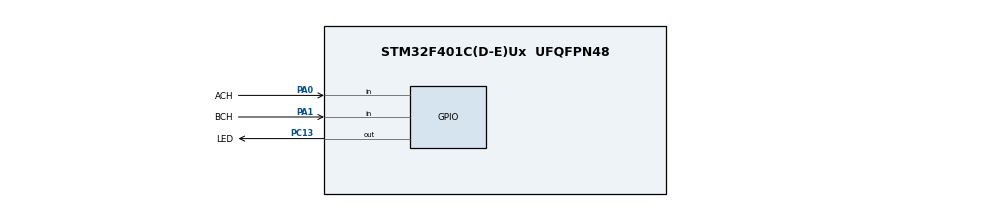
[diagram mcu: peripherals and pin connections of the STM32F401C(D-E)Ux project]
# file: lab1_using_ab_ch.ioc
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Mcu.Family=STM32F4
Mcu.Name=STM32F401C(D-E)Ux
Mcu.Package=UFQFPN48
NVIC.PriorityGroup=NVIC_PRIORITYGROUP_4
PA0-WKUP.GPIO_Label=ACH
PA0-WKUP.Signal=GPIO_Input
PA1.GPIO_Label=BCH
PA1.Signal=GPIO_Input
PA13.Mode=Serial_Wire
PA13.Signal=SYS_JTMS-SWDIO
PA14.Mode=Serial_Wire
PA14.Signal=SYS_JTCK-SWCLK
PC13-ANTI_TAMP.GPIO_Label=LED
PC13-ANTI_TAMP.Signal=GPIO_Output
PH0\ -\ OSC_IN.Mode=HSE-External-Oscillator
PH0\ -\ OSC_IN.Signal=RCC_OSC_IN
PH1\ -\ OSC_OUT.Mode=HSE-External-Oscillator
PH1\ -\ OSC_OUT.Signal=RCC_OSC_OUT
ProjectManager.HeapSize=0x200
ProjectManager.StackSize=0x400
ProjectManager.TargetToolchain=STM32CubeIDE
RCC.48MHZClocksFreq_Value=42000000
RCC.AHBFreq_Value=84000000
RCC.APB1CLKDivider=RCC_HCLK_DIV2
RCC.APB1Freq_Value=42000000
RCC.APB1TimFreq_Value=84000000
RCC.APB2Freq_Value=84000000
RCC.APB2TimFreq_Value=84000000
RCC.CortexFreq_Value=84000000
RCC.HCLKFreq_Value=84000000
RCC.HSE_VALUE=25000000
RCC.HSI_VALUE=16000000
RCC.PLLM=8
RCC.PLLN=84
RCC.SYSCLKFreq_VALUE=84000000
RCC.SYSCLKSource=RCC_SYSCLKSOURCE_PLLCLK
RCC.VCOOutputFreq_Value=168000000
board=custom

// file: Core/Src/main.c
/* USER CODE BEGIN Header */
/**
  ******************************************************************************
  * @file           : main.c
  * @brief          : Main program body
  ******************************************************************************
  * @attention
  *
  * Copyright (c) 2025 STMicroelectronics.
  * All rights reserved.
  *
  * This software is licensed under terms that can be found in the LICENSE file
  * in the root directory of this software component.
  * If no LICENSE file comes with this software, it is provided AS-IS.
  *
  ******************************************************************************
  */
/* USER CODE END Header */
#include "main.h"
#include "usb_device.h"

/* USER CODE BEGIN Includes */
#include "usbd_cdc_if.h"
#include "stdio.h"
extern uint8_t UserTxBufferFS[APP_TX_DATA_SIZE];

/* USER CODE END Includes */

/* USER CODE BEGIN PD */
uint16_t A_raw = 0;
uint16_t B_raw = 0;
float angle = 0;

typedef struct {
    int steps_per_revolution;
    int position;
    uint16_t prev_A;
    uint16_t prev_B;
    int last_position;
    uint32_t last_update_time;
    float speed;
} QuadratureEncoder;

void QuadratureEncoder_Init(QuadratureEncoder *encoder, int steps_per_revolution) {
    encoder->steps_per_revolution = steps_per_revolution;
    encoder->position = 0;
    encoder->prev_A = 0;
    encoder->prev_B = 0;
    encoder->last_position = 0;
    encoder->last_update_time = HAL_GetTick();
    encoder->speed = 0.0f;
}

void QuadratureEncoder_Update(QuadratureEncoder *encoder, uint16_t A_raw, uint16_t B_raw) {
    uint16_t A = A_raw;
    uint16_t B = B_raw;

    uint16_t state = (encoder->prev_A << 1) | encoder->prev_B;
    uint16_t new_state = (A << 1) | B;

    // Determine the delta based on state transitions
    int16_t delta = 0;
    if (state == 0b00) {
        if (new_state == 0b01) delta = 1;
        else if (new_state == 0b10) delta = -1;
    } else if (state == 0b01) {
        if (new_state == 0b11) delta = 1;
        else if (new_state == 0b00) delta = -1;
    } else if (state == 0b10) {
        if (new_state == 0b00) delta = 1;
        else if (new_state == 0b11) delta = -1;
    } else if (state == 0b11) {
        if (new_state == 0b10) delta = 1;
        else if (new_state == 0b01) delta = -1;
    }

    encoder->position += delta;

    encoder->prev_A = A;
    encoder->prev_B = B;

    // Calculate speed
    uint32_t current_time = HAL_GetTick();
    uint32_t dt = current_time - encoder->last_update_time; // Time difference in milliseconds

    if (dt > 0) {
        int position_change = encoder->position - encoder->last_position;
        encoder->speed = (1000.0f * position_change) / dt; // Speed in steps per second
    }

    // Update last position and time
    encoder->last_position = encoder->position;
    encoder->last_update_time = current_time;
}

float QuadratureEncoder_GetAngle(QuadratureEncoder *encoder) {
    return ((float)encoder->position / encoder->steps_per_revolution) * 360.0f;
}

QuadratureEncoder encoder;

/* USER CODE END PD */

void SystemClock_Config(void);
static void MX_GPIO_Init(void);

int main(void)
{

  /* MCU Configuration--------------------------------------------------------*/

  /* Reset of all peripherals, Initializes the Flash interface and the Systick. */
  HAL_Init();

  /* Configure the system clock */
  SystemClock_Config();

  /* Initialize all configured peripherals */
  MX_GPIO_Init();
  MX_USB_DEVICE_Init();
  /* USER CODE BEGIN 2 */
  QuadratureEncoder_Init(&encoder, 80);
  /* USER CODE END 2 */

  /* Infinite loop */
  while (1)
  {

    /* USER CODE BEGIN 3 */

	  A_raw = HAL_GPIO_ReadPin(ACH_GPIO_Port, ACH_Pin);
	  B_raw = HAL_GPIO_ReadPin(BCH_GPIO_Port, BCH_Pin);

	  QuadratureEncoder_Update(&encoder, A_raw, B_raw);

      angle = QuadratureEncoder_GetAngle(&encoder);

      snprintf(UserTxBufferFS, sizeof(UserTxBufferFS), "Speed: %.2f steps/s | Angle: %.2f°\r\n", encoder.speed, angle);

      /* Send data to USB CDC */
      CDC_Transmit_FS((uint8_t*)UserTxBufferFS, strlen(UserTxBufferFS));

      HAL_Delay(100); // Delay to prevent excessive printing

  }
  /* USER CODE END 3 */
}

void SystemClock_Config(void)
{
  RCC_OscInitTypeDef RCC_OscInitStruct = {0};
  RCC_ClkInitTypeDef RCC_ClkInitStruct = {0};

  /** Configure the main internal regulator output voltage
  */
  __HAL_RCC_PWR_CLK_ENABLE();
  __HAL_PWR_VOLTAGESCALING_CONFIG(PWR_REGULATOR_VOLTAGE_SCALE2);

  /** Initializes the RCC Oscillators according to the specified parameters
  * in the RCC_OscInitTypeDef structure.
  */
  RCC_OscInitStruct.OscillatorType = RCC_OSCILLATORTYPE_HSE;
  RCC_OscInitStruct.HSEState = RCC_HSE_ON;
  RCC_OscInitStruct.PLL.PLLState = RCC_PLL_ON;
  RCC_OscInitStruct.PLL.PLLSource = RCC_PLLSOURCE_HSE;
  RCC_OscInitStruct.PLL.PLLM = 15;
  RCC_OscInitStruct.PLL.PLLN = 144;
  RCC_OscInitStruct.PLL.PLLP = RCC_PLLP_DIV4;
  RCC_OscInitStruct.PLL.PLLQ = 5;
  if (HAL_RCC_OscConfig(&RCC_OscInitStruct) != HAL_OK)
  {
    Error_Handler();
  }

  /** Initializes the CPU, AHB and APB buses clocks
  */
  RCC_ClkInitStruct.ClockType = RCC_CLOCKTYPE_HCLK|RCC_CLOCKTYPE_SYSCLK
                              |RCC_CLOCKTYPE_PCLK1|RCC_CLOCKTYPE_PCLK2;
  RCC_ClkInitStruct.SYSCLKSource = RCC_SYSCLKSOURCE_PLLCLK;
  RCC_ClkInitStruct.AHBCLKDivider = RCC_SYSCLK_DIV1;
  RCC_ClkInitStruct.APB1CLKDivider = RCC_HCLK_DIV2;
  RCC_ClkInitStruct.APB2CLKDivider = RCC_HCLK_DIV1;

  if (HAL_RCC_ClockConfig(&RCC_ClkInitStruct, FLASH_LATENCY_1) != HAL_OK)
  {
    Error_Handler();
  }
}

static void MX_GPIO_Init(void)
{
  GPIO_InitTypeDef GPIO_InitStruct = {0};

  /* GPIO Ports Clock Enable */
  __HAL_RCC_GPIOC_CLK_ENABLE();
  __HAL_RCC_GPIOH_CLK_ENABLE();
  __HAL_RCC_GPIOA_CLK_ENABLE();

  /*Configure GPIO pin Output Level */
  HAL_GPIO_WritePin(LED_GPIO_Port, LED_Pin, GPIO_PIN_RESET);

  /*Configure GPIO pin : LED_Pin */
  GPIO_InitStruct.Pin = LED_Pin;
  GPIO_InitStruct.Mode = GPIO_MODE_OUTPUT_PP;
  GPIO_InitStruct.Pull = GPIO_NOPULL;
  GPIO_InitStruct.Speed = GPIO_SPEED_FREQ_LOW;
  HAL_GPIO_Init(LED_GPIO_Port, &GPIO_InitStruct);

  /*Configure GPIO pins : ACH_Pin BCH_Pin */
  GPIO_InitStruct.Pin = ACH_Pin|BCH_Pin;
  GPIO_InitStruct.Mode = GPIO_MODE_INPUT;
  GPIO_InitStruct.Pull = GPIO_NOPULL;
  HAL_GPIO_Init(GPIOA, &GPIO_InitStruct);

}

void Error_Handler(void)
{
  __disable_irq();
  while (1)
  {
  }
}
